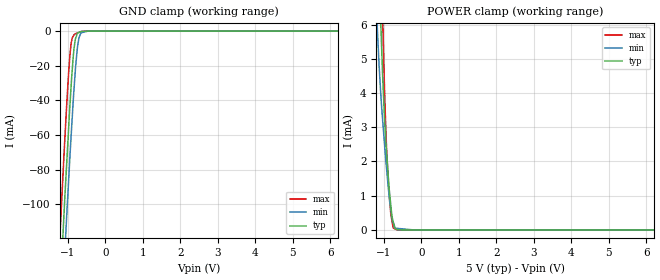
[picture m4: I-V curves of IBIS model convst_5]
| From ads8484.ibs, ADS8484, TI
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|   convst_5 Model
[Model]   convst_5
Model_type   Input
Vinl = 0.8
Vinh = 4.0
|   typ   min   max
|   (nom PVT)   (Fast PVT)   (slow PVT)
|C_comp from frequency method(F=1MHz)
|Average
|C_comp   1.363e-12   1.257e-12   1.476e-12
|C_comp from L-C Tank method(L=1nH)
|Resonant Frequency(Hz)   4.79e9   4.86e9   4.72e9
C_comp   1.105e-12   1.073e-12   1.138e-12
| Where nom  PVT is Nominal Process,  5V,  30C
|   Fast PVT is Strong Process,   5.25V,  -40C
|   Slow PVT is Weak Process,   4.75V,  90C
[Model Spec]
Vinl   0.8   0.8   0.8
Vinh   4.0   3.75   4.25
[Voltage Range]   5   4.75   5.25
|Ambient Temperature   25   85   -40
|Junction Temperature
[Temperature Range]   30   90   -40
[Power Clamp Reference]   5   4.75   5.25
[GND Clamp Reference]   0   0   0
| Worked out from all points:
|   GND clamp passes 1 mA (typ) near -0.73 V on its own axis
|   POWER clamp passes 1 mA (typ) near -0.84 V on its own axis
[GND Clamp]
|   Voltage   I(typ)   I(min)   I(max)
-5V       -1.898A    -1.916A    -1.876A
-1.306V   -192.2mA   -223.1mA   -158.4mA
-1.108V   -106.7mA   -138mA     -72.38mA
-1.08V    -94.88mA   -126.2mA   -61.18mA
-1.04V    -78.88mA   -109.4mA   -44.94mA
-950.3mV  -43.75mA   -73.69mA   -14.72mA
-913.5mV  -31.06mA   -60mA      -6.967mA
-840mV    -10.48mA   -34.09mA   -2.163mA
-745.8mV  -1.183mA   -9.257mA   -1.102mA
-707.7mV  -789.6uA   -4.052mA   -791.6uA
-640mV    -158.4uA   -951.7uA   -242uA
10V       0A         0A         0A
[POWER Clamp]
|   Voltage   I(typ)   I(min)   I(max)
-5V       200.2mA    168.8mA    246.3mA
-1.178V   10.06mA    6.005mA    13.91mA
-1.08V    6.013mA    3.952mA    8.603mA
-1.064V   5.51mA     3.682mA    7.807mA
-1.035V   4.599mA    3.255mA    6.396mA
-990mV    3.456mA    2.619mA    4.468mA
-929.3mV  2.319mA    1.811mA    2.435mA
-876.8mV  1.492mA    1.196mA    1.331mA
-813.7mV  723.3uA    596.6uA    459.2uA
-750.8mV  240uA      226.2uA    58.49uA
-640.5mV  4.904uA    46.48uA    457nA
10V       0A         0A         0A
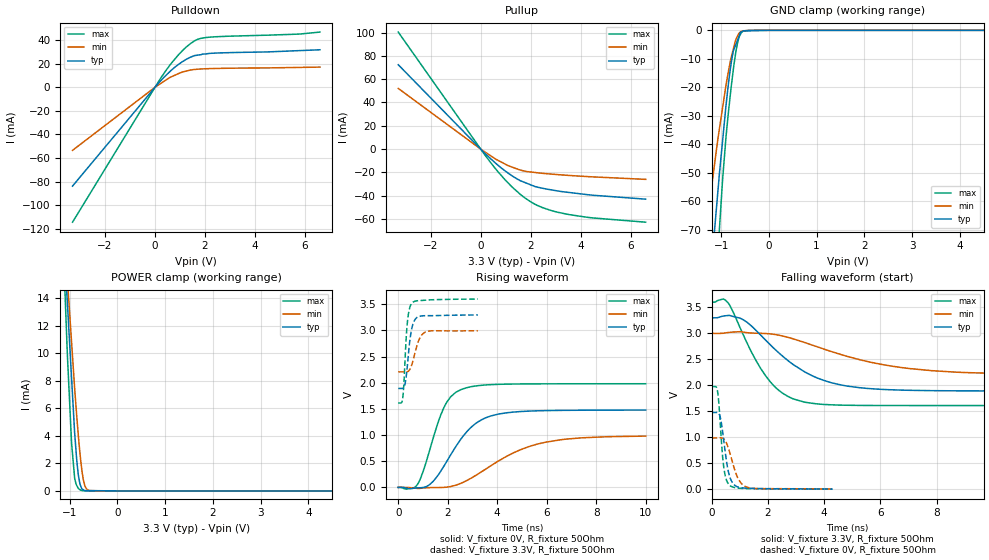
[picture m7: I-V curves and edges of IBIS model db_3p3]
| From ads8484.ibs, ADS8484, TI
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|   db_3p3 Model
[Model]   db_3p3
Model_type   3-state
Polarity   Non-Inverting
Vmeas = 1.65
Vref = 1.65
Cref = 5pF
Rref = 50
|   typ   min   max
|   (nom PVT)   (Fast PVT)   (slow PVT)
|C_comp from frequency method(F=1MHz)
|Average
|C_comp   8.585e-12   7.603e-12   1.501e-11
|ON state : BUFFER OUTPUT TURNED HIGH
|C_comp   8.585e-12   7.603e-12   1.501e-11
|OFF state: BUFFER IN HIGH IMPEDANCE
|C_comp   3.160e-12   2.310e-12   4.051e-12
|C_comp from L-C Tank method(L=1nH)
|Resonant Frequency(Hz)   3.39e9   3.84e9   3.04e9
C_comp   2.206e-12   1.720e-12   2.744e-12
| Where nom  PVT is Nominal Process,  3.3V,  30C
|   Fast PVT is Strong Process,   3.6V,  -40C
|   Slow PVT is Weak Process,   3V,  90C
[Voltage Range]   3.3   3   3.6
|Ambient Temperature   25   85   -40
|Junction Temperature
[Temperature Range]   30   90   -40
[Pullup Reference]   3.3   3   3.6
[Pulldown Reference]   0   0   0
[Power Clamp Reference]   3.3   3   3.6
[GND Clamp Reference]   0   0   0
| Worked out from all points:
|   slope of the pulldown table from 0 to 0.495 V, typ, clamps not added: 44 ohm
|   slope of the pullup table from 0 to 0.495 V, typ, clamps not added: 48.8 ohm
|   GND clamp passes 1 mA (typ) near -0.60 V on its own axis
|   POWER clamp passes 1 mA (typ) near -0.81 V on its own axis
|   falling waveform, V_fixture 3.3V, R_fixture 50Ohm: 20-80 % time 1.98ns typ, 3.21ns min, 1.25ns max; typ from 3.3 V to 1.89 V
|   rising waveform, V_fixture 0V, R_fixture 50Ohm: 20-80 % time 1.33ns typ, 2.29ns min, 839ps max; typ from 0 V to 1.48 V
|   rising waveform, V_fixture 3.3V, R_fixture 50Ohm: 20-80 % time 202ps typ, 293ps min, 150ps max; typ from 1.89 V to 3.29 V
|   falling waveform, V_fixture 0V, R_fixture 50Ohm: 20-80 % time 242ps typ, 350ps min, 172ps max; typ from 1.48 V to 0.004 V
[Pulldown]
|   Voltage   I(typ)   I(min)   I(max)
-3.3V     -83.89mA   -53.54mA   -114.5mA
18mV      442.5uA    290.8uA    632.8uA
277.2mV   6.675mA    3.919mA    9.305mA
633.6mV   14.11mA    8.701mA    19.85mA
939.6mV   19.42mA    11.62mA    27.58mA
1.422V    25.55mA    14.66mA    37.14mA
1.706V    27.29mA    15.33mA    40.71mA
2.167V    28.73mA    15.83mA    42.5mA
5.774V    31.12mA    16.85mA    45.16mA
6.6V      31.84mA    17.12mA    46.85mA
[GND Clamp]
|   Voltage   I(typ)   I(min)   I(max)
-3.3V     -561.8mA   -397.1mA   -773.2mA
-1.372V   -118mA     -78.17mA   -168.5mA
-1.266V   -95.9mA    -63.37mA   -137.2mA
-1.208V   -83.76mA   -55.94mA   -120mA
-1.068V   -56.57mA   -38.13mA   -78.57mA
-1.036V   -50.39mA   -34.6mA    -69.89mA
-896.4mV  -26.15mA   -19.09mA   -37.12mA
-778.8mV  -10.35mA   -8.829mA   -18.45mA
-684mV    -4.663mA   -2.91mA    -6.792mA
-591mV    -668.1uA   -487.2uA   -1.249mA
-439.2mV  -159.7uA   -95.48uA   -12.8uA
6.6V      0A         0A         0A
[Pullup]
|   Voltage   I(typ)   I(min)   I(max)
-3.3V     72.4mA     52.08mA    100.4mA
18mV      -386.8uA   -283.2uA   -546.9uA
478.8mV   -9.824mA   -6.877mA   -13.81mA
939.6mV   -18.13mA   -12.42mA   -25.51mA
1.235V    -22.64mA   -15.28mA   -32.07mA
1.706V    -28.15mA   -18.63mA   -40.89mA
2.239V    -32.46mA   -20.22mA   -48.04mA
3.089V    -35.94mA   -21.9mA    -54.2mA
4.497V    -39.59mA   -23.84mA   -59.06mA
6.6V      -42.95mA   -25.96mA   -62.7mA
[POWER Clamp]
|   Voltage   I(typ)   I(min)   I(max)
-3.3V     145.1mA    127.5mA    169.4mA
-1.102V   16.95mA    18.16mA    14.73mA
-1.051V   13.79mA    15.5mA     10.09mA
-961.2mV  8.212mA    10.81mA    3.494mA
-896.4mV  4.215mA    7.438mA    921.9uA
-858mV    2.468mA    5.669mA    431.4uA
-818.4mV  1.143mA    3.998mA    182.3uA
-770.4mV  363.7uA    2.238mA    58.37uA
-738mV    134.6uA    1.308mA    24.21uA
-684mV    26.47uA    389.8uA    5.069uA
-591mV    22.85uA    25.75uA    3.144uA
6.6V      0A         0A         0A
[Ramp]
R_load = 50
|   typ   min   max
dV/dt_r   0.886173/1.32675e-09   0.587642/2.29238e-09   1.18781/8.3853e-10
dV/dt_f   0.844308/1.96558e-09   0.461379/3.05001e-09   1.1933/1.24375e-09
[Falling Waveform]
V_fixture = 3.3V
V_fixture_min = 3V
V_fixture_max = 3.6V
R_fixture = 50Ohm
|   Time   V(typ)   V(min)   V(max)
0s        3.3V       3V         3.6V
410ps     3.333V     3.003V     3.66V
590ps     3.345V     3.016V     3.587V
1.24ns    3.223V     3.015V     2.84V
1.94ns    2.86V      2.996V     2.17V
2.53ns    2.56V      2.949V     1.848V
3.29ns    2.266V     2.828V     1.679V
4.73ns    1.995V     2.572V     1.618V
7.04ns    1.904V     2.323V     1.612V
13.02ns   1.891V     2.212V     1.611V
[Rising Waveform]
V_fixture = 0V
V_fixture_min = 0V
V_fixture_max = 0V
R_fixture = 50Ohm
|   Time   V(typ)   V(min)   V(max)
0s        1.236nV    1.432nV    1.107nV
330ps     -14.84mV   360uV      -34.04mV
780ps     -8.903mV   -19.55mV   58.19mV
1.28ns    57.85mV    -4.993mV   726.3mV
1.82ns    385.6mV    -629.9uV   1.499V
2.12ns    622mV      16.48mV    1.731V
2.53ns    920.6mV    77.37mV    1.867V
3.52ns    1.326V     345.1mV    1.956V
5.61ns    1.463V     825.1mV    1.977V
10ns      1.477V     979.4mV    1.98V
[Rising Waveform]
V_fixture = 3.3V
V_fixture_min = 3V
V_fixture_max = 3.6V
R_fixture = 50Ohm
|   Time   V(typ)   V(min)   V(max)
0s        1.89V      2.207V     1.611V
180ps     1.89V      2.207V     1.697V
220ps     1.902V     2.207V     1.918V
280ps     1.986V     2.206V     2.479V
370ps     2.33V      2.21V      3.152V
440ps     2.684V     2.234V     3.385V
540ps     3.019V     2.331V     3.511V
810ps     3.26V      2.786V     3.566V
1.08ns    3.28V      2.963V     3.575V
3.22ns    3.294V     2.992V     3.597V
[Falling Waveform]
V_fixture = 0V
V_fixture_min = 0V
V_fixture_max = 0V
R_fixture = 50Ohm
|   Time   V(typ)   V(min)   V(max)
0s        1.477V     987.8mV    1.976V
210ps     1.477V     987.6mV    1.891V
250ps     1.463V     988.2mV    1.708V
310ps     1.383V     989.8mV    1.26V
430ps     955.1mV    970.8mV    439.9mV
520ps     580.1mV    899.9mV    192.9mV
630ps     272.2mV    736.2mV    83.06mV
920ps     46.88mV    232.8mV    23.04mV
1.22ns    21.11mV    48.89mV    13.64mV
4.3ns     4.255mV    5.958mV    1.893mV
